# Autogenerated file; please don't edit
# date: 2024-05-13 13:33:05.137460

########################################################################
#
# Copyright 2024 IHP PDK Authors
# 
# Licensed under the Apache License, Version 2.0 (the "License");
# you may not use this file except in compliance with the License.
# You may obtain a copy of the License at
# 
#    https://www.apache.org/licenses/LICENSE-2.0
# 
# Unless required by applicable law or agreed to in writing, software
# distributed under the License is distributed on an "AS IS" BASIS,
# WITHOUT WARRANTIES OR CONDITIONS OF ANY KIND, either express or implied.
# See the License for the specific language governing permissions and
# limitations under the License.
#
########################################################################

VERSION 5.7 ;

SITE sg13cmos5l_ioSite
    CLASS PAD ;
    SYMMETRY R90 ;
    SIZE 1.00 BY 180.00 ;
END sg13cmos5l_ioSite

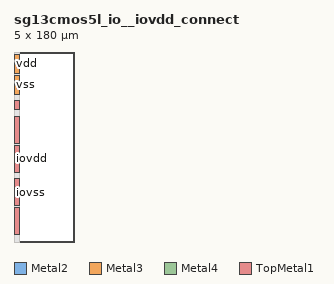
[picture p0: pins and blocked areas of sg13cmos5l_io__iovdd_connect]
MACRO sg13cmos5l_io__iovdd_connect
    CLASS PAD SPACER ;
    ORIGIN 0.000 0.000 ;
    FOREIGN sg13cmos5l_io__iovdd_connect 0.000 0.000 ;
    SIZE 5.000 BY 180.000 ;
    SYMMETRY X Y R90 ;
    SITE sg13cmos5l_ioSite ;
  PIN iovdd
    DIRECTION INOUT ;
    USE POWER ;
    PORT
      LAYER Metal2 ;
        RECT 0.500 177.500 4.500 178.000 ;
    END
    PORT
      LAYER Metal3 ;
        RECT 0.000 66.000 5.000 91.500 ;
    END
    PORT
      LAYER Metal3 ;
        RECT 0.000 93.500 5.000 119.000 ;
    END
    PORT
      LAYER Metal4 ;
        RECT 0.000 66.000 5.000 91.500 ;
    END
    PORT
      LAYER Metal4 ;
        RECT 0.000 93.500 5.000 119.000 ;
    END
    PORT
      LAYER TopMetal1 ;
        RECT 0.000 66.000 5.000 91.500 ;
    END
    PORT
      LAYER TopMetal1 ;
        RECT 0.000 93.500 5.000 119.000 ;
    END
  END iovdd
  PIN iovss
    DIRECTION INOUT ;
    USE GROUND ;
    PORT
      LAYER Metal3 ;
        RECT 0.000 34.500 5.000 60.000 ;
    END
    PORT
      LAYER Metal3 ;
        RECT 0.000 7.000 5.000 32.500 ;
    END
    PORT
      LAYER Metal3 ;
        RECT 0.000 126.000 5.000 134.000 ;
    END
    PORT
      LAYER Metal4 ;
        RECT 0.000 34.500 5.000 60.000 ;
    END
    PORT
      LAYER Metal4 ;
        RECT 0.000 7.000 5.000 32.500 ;
    END
    #PORT
    #  LAYER Metal4 ;
    #    RECT 0.000 126.000 5.000 134.000 ;
    #END
    PORT
      LAYER TopMetal1 ;
        RECT 0.000 34.500 5.000 60.000 ;
    END
    PORT
      LAYER TopMetal1 ;
        RECT 0.000 7.000 5.000 32.500 ;
    END
    PORT
      LAYER TopMetal1 ;
        RECT 0.000 126.000 5.000 134.000 ;
    END
  END iovss
  PIN vdd
    DIRECTION INOUT ;
    USE POWER ;
    PORT
      LAYER Metal3 ;
        RECT 0.000 160.000 5.000 178.000 ;
    END
    #PORT
    #  LAYER Metal4 ;
    #    RECT 0.000 140.000 5.000 155.800 ;
    #END
  END vdd
  PIN vss
    DIRECTION INOUT ;
    USE GROUND ;
    PORT
      LAYER Metal3 ;
        RECT 0.000 140.000 5.000 158.000 ;
    END
    #PORT
    #  LAYER Metal4 ;
    #    RECT 0.000 162.200 5.000 178.000 ;
    #END
  END vss
  OBS
    LAYER Metal1 ;
      RECT 0.000 0.000 5.000 180.000 ;
    LAYER Metal2 ;
      RECT 0.000 0.000 5.000 178.000 ;
    LAYER Metal3 ;
      RECT 0.000 0.000 5.000 178.000 ;
    LAYER Metal4 ;
      RECT 0.000 0.000 5.000 178.000 ;
    LAYER TopMetal1 ;
      RECT 0.000 0.000 5.000 134.500 ;
    LAYER Via1 ;
      RECT 0.000 0.000 5.000 180.000 ;
    LAYER Via2 ;
      RECT 0.000 0.000 5.000 180.000 ;
  END
END sg13cmos5l_io__iovdd_connect
